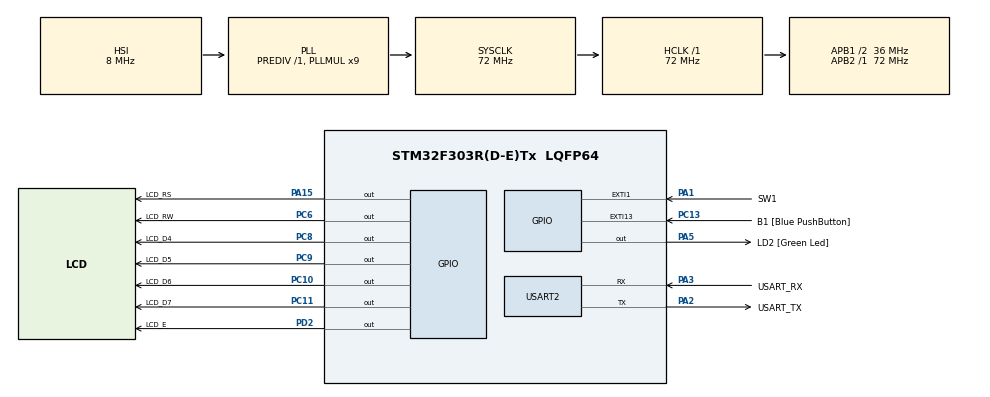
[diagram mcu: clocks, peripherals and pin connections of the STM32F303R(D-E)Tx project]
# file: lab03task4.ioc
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Mcu.Family=STM32F3
Mcu.Name=STM32F303R(D-E)Tx
Mcu.Package=LQFP64
NVIC.EXTI1_IRQn=true\:0\:0\:false\:false\:true\:true\:true\:true
NVIC.PriorityGroup=NVIC_PRIORITYGROUP_0
NVIC.TIM6_DAC_IRQn=true\:0\:0\:false\:false\:true\:true\:true\:true
PA1.GPIO_Label=SW1
PA1.Signal=GPXTI1
PA13.GPIO_Label=TMS
PA13.Mode=Serial_Wire
PA13.Signal=SYS_JTMS-SWDIO
PA14.GPIO_Label=TCK
PA14.Mode=Serial_Wire
PA14.Signal=SYS_JTCK-SWCLK
PA15.GPIO_Label=LCD_RS
PA15.Signal=GPIO_Output
PA2.GPIO_Label=USART_TX
PA2.GPIO_Mode=GPIO_MODE_AF_PP
PA2.GPIO_PuPd=GPIO_NOPULL
PA2.GPIO_Speed=GPIO_SPEED_FREQ_LOW
PA2.Mode=Asynchronous
PA2.Signal=USART2_TX
PA3.GPIO_Label=USART_RX
PA3.GPIO_Mode=GPIO_MODE_AF_PP
PA3.GPIO_PuPd=GPIO_NOPULL
PA3.GPIO_Speed=GPIO_SPEED_FREQ_LOW
PA3.Mode=Asynchronous
PA3.Signal=USART2_RX
PA5.GPIO_Label=LD2 [Green Led]
PA5.GPIO_Mode=GPIO_MODE_OUTPUT_PP
PA5.GPIO_PuPd=GPIO_NOPULL
PA5.GPIO_Speed=GPIO_SPEED_FREQ_LOW
PA5.Signal=GPIO_Output
PB3.GPIO_Label=SWO
PB3.Signal=SYS_JTDO-TRACESWO
PC10.GPIO_Label=LCD_D6
PC10.Signal=GPIO_Output
PC11.GPIO_Label=LCD_D7
PC11.Signal=GPIO_Output
PC13.GPIO_Label=B1 [Blue PushButton]
PC13.GPIO_ModeDefaultEXTI=GPIO_MODE_IT_FALLING
PC13.Signal=GPXTI13
PC14-OSC32_IN.Mode=LSE-External-Oscillator
PC14-OSC32_IN.Signal=RCC_OSC32_IN
PC15-OSC32_OUT.Mode=LSE-External-Oscillator
PC15-OSC32_OUT.Signal=RCC_OSC32_OUT
PC6.GPIO_Label=LCD_RW
PC6.Signal=GPIO_Output
PC8.GPIO_Label=LCD_D4
PC8.Signal=GPIO_Output
PC9.GPIO_Label=LCD_D5
PC9.Signal=GPIO_Output
PD2.GPIO_Label=LCD_E
PD2.Signal=GPIO_Output
PF0-OSC_IN.Mode=HSE-External-Clock-Source
PF0-OSC_IN.Signal=RCC_OSC_IN
PF1-OSC_OUT.Signal=RCC_OSC_OUT
ProjectManager.HeapSize=0x200
ProjectManager.StackSize=0x400
ProjectManager.TargetToolchain=STM32CubeIDE
RCC.AHBFreq_Value=72000000
RCC.APB1CLKDivider=RCC_HCLK_DIV2
RCC.APB1Freq_Value=36000000
RCC.APB1TimFreq_Value=72000000
RCC.APB2Freq_Value=72000000
RCC.APB2TimFreq_Value=72000000
RCC.CortexFreq_Value=72000000
RCC.HCLKFreq_Value=72000000
RCC.HSE_VALUE=8000000
RCC.HSI_VALUE=8000000
RCC.PLLM=8
RCC.PLLMUL=RCC_PLL_MUL9
RCC.PLLN=336
RCC.PLLP=RCC_PLLP_DIV4
RCC.PLLQ=7
RCC.RCC_PLLsource_Clock_Source_FROM_HSE=RCC_HSE_PREDIV_DIV2
RCC.SYSCLKFreq_VALUE=72000000
RCC.SYSCLKSourceVirtual=RCC_SYSCLKSOURCE_PLLCLK
RCC.USBFreq_Value=72000000
TIM6.Period=7199
TIM6.Prescaler=9999
USART2.VirtualMode-Asynchronous=VM_ASYNC
VP_TIM6_VS_ClockSourceINT.Mode=Enable_Timer
board=NUCLEO-F303RE

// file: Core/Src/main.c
/* USER CODE BEGIN Header */
/**
  ******************************************************************************
  * @file           : main.c
  * @brief          : Main program body
  ******************************************************************************
  * @attention
  *
  * Copyright (c) 2024 STMicroelectronics.
  * All rights reserved.
  *
  * This software is licensed under terms that can be found in the LICENSE file
  * in the root directory of this software component.
  * If no LICENSE file comes with this software, it is provided AS-IS.
  *
  ******************************************************************************
  */
/* USER CODE END Header */
#include "main.h"

/* USER CODE BEGIN Includes */
#include <string.h>
#include <stdio.h>
/* USER CODE END Includes */

TIM_HandleTypeDef htim6;

UART_HandleTypeDef huart2;

/* USER CODE BEGIN PV */
//volatile uint32_t startTime = 0;
//volatile uint32_t endTime = 0;
//volatile uint32_t duration = 0;

volatile uint32_t counter = 0;
/* USER CODE END PV */

void SystemClock_Config(void);
static void MX_GPIO_Init(void);
static void MX_USART2_UART_Init(void);
static void MX_TIM6_Init(void);
/* USER CODE BEGIN PFP */
void LCD_putNibble(uint8_t data);
void LCD_enable();
void LCD_command(uint8_t command);
void LCD_data(uint8_t data);
void LCD_display(const char *str);
/* USER CODE END PFP */

int main(void)
{

  /* MCU Configuration--------------------------------------------------------*/

  /* Reset of all peripherals, Initializes the Flash interface and the Systick. */
  HAL_Init();

  /* Configure the system clock */
  SystemClock_Config();

  /* Initialize all configured peripherals */
  MX_GPIO_Init();
  MX_USART2_UART_Init();
  MX_TIM6_Init();
  /* USER CODE BEGIN 2 */
  HAL_Delay(50);
  LCD_putNibble(0b0011);
  LCD_enable();
  LCD_putNibble(0b0011);
  LCD_enable();
  LCD_putNibble(0b0011);
  LCD_enable();
  LCD_putNibble(0b0010);
  LCD_enable();
  LCD_command(0b00101100);
  LCD_command(0b00001000);
  LCD_command(0b00000001);
  LCD_command(0b00000110);
  LCD_command(0b00001111);

  LCD_display("Press SW1/2/3 to Start");
  /* USER CODE END 2 */

  /* Infinite loop */
  while (1)
  {

  }
}

void SystemClock_Config(void)
{
  RCC_OscInitTypeDef RCC_OscInitStruct = {0};
  RCC_ClkInitTypeDef RCC_ClkInitStruct = {0};
  RCC_PeriphCLKInitTypeDef PeriphClkInit = {0};

  /** Initializes the RCC Oscillators according to the specified parameters
  * in the RCC_OscInitTypeDef structure.
  */
  RCC_OscInitStruct.OscillatorType = RCC_OSCILLATORTYPE_HSI;
  RCC_OscInitStruct.HSIState = RCC_HSI_ON;
  RCC_OscInitStruct.HSICalibrationValue = RCC_HSICALIBRATION_DEFAULT;
  RCC_OscInitStruct.PLL.PLLState = RCC_PLL_ON;
  RCC_OscInitStruct.PLL.PLLSource = RCC_PLLSOURCE_HSI;
  RCC_OscInitStruct.PLL.PLLMUL = RCC_PLL_MUL9;
  RCC_OscInitStruct.PLL.PREDIV = RCC_PREDIV_DIV1;
  if (HAL_RCC_OscConfig(&RCC_OscInitStruct) != HAL_OK)
  {
    Error_Handler();
  }

  /** Initializes the CPU, AHB and APB buses clocks
  */
  RCC_ClkInitStruct.ClockType = RCC_CLOCKTYPE_HCLK|RCC_CLOCKTYPE_SYSCLK
                              |RCC_CLOCKTYPE_PCLK1|RCC_CLOCKTYPE_PCLK2;
  RCC_ClkInitStruct.SYSCLKSource = RCC_SYSCLKSOURCE_PLLCLK;
  RCC_ClkInitStruct.AHBCLKDivider = RCC_SYSCLK_DIV1;
  RCC_ClkInitStruct.APB1CLKDivider = RCC_HCLK_DIV2;
  RCC_ClkInitStruct.APB2CLKDivider = RCC_HCLK_DIV1;

  if (HAL_RCC_ClockConfig(&RCC_ClkInitStruct, FLASH_LATENCY_2) != HAL_OK)
  {
    Error_Handler();
  }
  PeriphClkInit.PeriphClockSelection = RCC_PERIPHCLK_USART2;
  PeriphClkInit.Usart2ClockSelection = RCC_USART2CLKSOURCE_PCLK1;
  if (HAL_RCCEx_PeriphCLKConfig(&PeriphClkInit) != HAL_OK)
  {
    Error_Handler();
  }
}

static void MX_TIM6_Init(void)
{

  TIM_MasterConfigTypeDef sMasterConfig = {0};

  htim6.Instance = TIM6;
  htim6.Init.Prescaler = 99;
  htim6.Init.CounterMode = TIM_COUNTERMODE_UP;
  htim6.Init.Period = 719;
  htim6.Init.AutoReloadPreload = TIM_AUTORELOAD_PRELOAD_DISABLE;
  if (HAL_TIM_Base_Init(&htim6) != HAL_OK)
  {
    Error_Handler();
  }
  sMasterConfig.MasterOutputTrigger = TIM_TRGO_RESET;
  sMasterConfig.MasterSlaveMode = TIM_MASTERSLAVEMODE_DISABLE;
  if (HAL_TIMEx_MasterConfigSynchronization(&htim6, &sMasterConfig) != HAL_OK)
  {
    Error_Handler();
  }

}

static void MX_USART2_UART_Init(void)
{

  huart2.Instance = USART2;
  huart2.Init.BaudRate = 38400;
  huart2.Init.WordLength = UART_WORDLENGTH_8B;
  huart2.Init.StopBits = UART_STOPBITS_1;
  huart2.Init.Parity = UART_PARITY_NONE;
  huart2.Init.Mode = UART_MODE_TX_RX;
  huart2.Init.HwFlowCtl = UART_HWCONTROL_NONE;
  huart2.Init.OverSampling = UART_OVERSAMPLING_16;
  huart2.Init.OneBitSampling = UART_ONE_BIT_SAMPLE_DISABLE;
  huart2.AdvancedInit.AdvFeatureInit = UART_ADVFEATURE_NO_INIT;
  if (HAL_UART_Init(&huart2) != HAL_OK)
  {
    Error_Handler();
  }

}

static void MX_GPIO_Init(void)
{
  GPIO_InitTypeDef GPIO_InitStruct = {0};

  /* GPIO Ports Clock Enable */
  __HAL_RCC_GPIOC_CLK_ENABLE();
  __HAL_RCC_GPIOF_CLK_ENABLE();
  __HAL_RCC_GPIOA_CLK_ENABLE();
  __HAL_RCC_GPIOD_CLK_ENABLE();
  __HAL_RCC_GPIOB_CLK_ENABLE();

  /*Configure GPIO pin Output Level */
  HAL_GPIO_WritePin(GPIOA, LD2_Pin|LCD_RS_Pin, GPIO_PIN_RESET);

  /*Configure GPIO pin Output Level */
  HAL_GPIO_WritePin(GPIOC, LCD_RW_Pin|LCD_D4_Pin|LCD_D5_Pin|LCD_D6_Pin
                          |LCD_D7_Pin, GPIO_PIN_RESET);

  /*Configure GPIO pin Output Level */
  HAL_GPIO_WritePin(LCD_E_GPIO_Port, LCD_E_Pin, GPIO_PIN_RESET);

  /*Configure GPIO pin : B1_Pin */
  GPIO_InitStruct.Pin = B1_Pin;
  GPIO_InitStruct.Mode = GPIO_MODE_IT_FALLING;
  GPIO_InitStruct.Pull = GPIO_NOPULL;
  HAL_GPIO_Init(B1_GPIO_Port, &GPIO_InitStruct);

  /*Configure GPIO pin : SW1_Pin */
  GPIO_InitStruct.Pin = SW1_Pin;
  GPIO_InitStruct.Mode = GPIO_MODE_IT_RISING_FALLING;
  GPIO_InitStruct.Pull = GPIO_NOPULL;
  HAL_GPIO_Init(SW1_GPIO_Port, &GPIO_InitStruct);

  /*Configure GPIO pin : SW2_Pin */
  GPIO_InitStruct.Pin = SW2_Pin;
  GPIO_InitStruct.Mode = GPIO_MODE_IT_RISING_FALLING;
  GPIO_InitStruct.Pull = GPIO_NOPULL;
  HAL_GPIO_Init(SW2_GPIO_Port, &GPIO_InitStruct);

  /*Configure GPIO pin : SW3_Pin */
  GPIO_InitStruct.Pin = SW3_Pin;
  GPIO_InitStruct.Mode = GPIO_MODE_IT_RISING_FALLING;
  GPIO_InitStruct.Pull = GPIO_NOPULL;
  HAL_GPIO_Init(SW3_GPIO_Port, &GPIO_InitStruct);

  /*Configure GPIO pins : LD2_Pin LCD_RS_Pin */
  GPIO_InitStruct.Pin = LD2_Pin|LCD_RS_Pin;
  GPIO_InitStruct.Mode = GPIO_MODE_OUTPUT_PP;
  GPIO_InitStruct.Pull = GPIO_NOPULL;
  GPIO_InitStruct.Speed = GPIO_SPEED_FREQ_LOW;
  HAL_GPIO_Init(GPIOA, &GPIO_InitStruct);

  /*Configure GPIO pins : LCD_RW_Pin LCD_D4_Pin LCD_D5_Pin LCD_D6_Pin
                           LCD_D7_Pin */
  GPIO_InitStruct.Pin = LCD_RW_Pin|LCD_D4_Pin|LCD_D5_Pin|LCD_D6_Pin
                          |LCD_D7_Pin;
  GPIO_InitStruct.Mode = GPIO_MODE_OUTPUT_PP;
  GPIO_InitStruct.Pull = GPIO_NOPULL;
  GPIO_InitStruct.Speed = GPIO_SPEED_FREQ_LOW;
  HAL_GPIO_Init(GPIOC, &GPIO_InitStruct);

  /*Configure GPIO pin : LCD_E_Pin */
  GPIO_InitStruct.Pin = LCD_E_Pin;
  GPIO_InitStruct.Mode = GPIO_MODE_OUTPUT_PP;
  GPIO_InitStruct.Pull = GPIO_NOPULL;
  GPIO_InitStruct.Speed = GPIO_SPEED_FREQ_LOW;
  HAL_GPIO_Init(LCD_E_GPIO_Port, &GPIO_InitStruct);

  /* EXTI interrupt init*/
  HAL_NVIC_SetPriority(EXTI1_IRQn, 0, 0);
  HAL_NVIC_EnableIRQ(EXTI1_IRQn);

  /* EXTI interrupt init*/
  HAL_NVIC_SetPriority(EXTI4_IRQn, 0, 0);
  HAL_NVIC_EnableIRQ(EXTI4_IRQn);

  /* EXTI interrupt init*/
  HAL_NVIC_SetPriority(EXTI0_IRQn, 0, 0);
  HAL_NVIC_EnableIRQ(EXTI0_IRQn);

}

/* USER CODE BEGIN 4 */
void HAL_GPIO_EXTI_Callback(uint16_t GPIO_Pin) {
	if (GPIO_Pin == SW1_Pin) {
		if (HAL_GPIO_ReadPin(SW1_GPIO_Port, SW1_Pin) == GPIO_PIN_SET) {
			HAL_TIM_Base_Start_IT(&htim6);
			char temp[20];
			sprintf(temp, "Time: %lu ms", counter);
			LCD_command(0b00000001);	// clear display;
			LCD_display(temp);
		} else {
			counter = 0;
		}
	}
	if (GPIO_Pin == SW2_Pin) {
		if (HAL_GPIO_ReadPin(SW1_GPIO_Port, SW2_Pin) == GPIO_PIN_SET) {
			HAL_TIM_Base_Start_IT(&htim6);
			char temp[20];
			sprintf(temp, "Time: %lu ms", counter);
			LCD_command(0b00000001);	// clear display;
			LCD_display(temp);
		} else {
			counter = 0;
		}
	}
	if (GPIO_Pin == SW3_Pin) {
			if (HAL_GPIO_ReadPin(SW1_GPIO_Port, SW3_Pin) == GPIO_PIN_SET) {
				HAL_TIM_Base_Start_IT(&htim6);
				char temp[20];
				sprintf(temp, "Time: %lu ms", counter);
				LCD_command(0b00000001);	// clear display;
				LCD_display(temp);
			} else {
				counter = 0;
			}
		}
}

void HAL_TIM_PeriodElapsedCallback(TIM_HandleTypeDef *htim) {
    counter++;
}

void LCD_putNibble(uint8_t data) {
	HAL_GPIO_WritePin(LCD_D4_GPIO_Port, LCD_D4_Pin, data & 1);
	HAL_GPIO_WritePin(LCD_D5_GPIO_Port, LCD_D5_Pin, (data >> 1) & 1);
	HAL_GPIO_WritePin(LCD_D6_GPIO_Port, LCD_D6_Pin, (data >> 2) & 1);
	HAL_GPIO_WritePin(LCD_D7_GPIO_Port, LCD_D7_Pin, (data >> 3) & 1);
}

void LCD_enable() {
	HAL_GPIO_WritePin(LCD_E_GPIO_Port, LCD_E_Pin, 1);
	int delayCounter = 10000;
	while(delayCounter--);
	HAL_GPIO_WritePin(LCD_E_GPIO_Port, LCD_E_Pin, 0);
	delayCounter = 10000;
	while(delayCounter--);
}

void LCD_command(uint8_t command) {
	HAL_GPIO_WritePin(LCD_RS_GPIO_Port, LCD_RS_Pin, 0);
	LCD_putNibble(command >> 4);
	LCD_enable();
	LCD_putNibble(command & 0x0f);
	LCD_enable();
}

void LCD_data(uint8_t data) {
	HAL_GPIO_WritePin(LCD_RS_GPIO_Port, LCD_RS_Pin, 1);
	int delayCounter = 10000;
	while(delayCounter--);
	LCD_putNibble(data >> 4);
	LCD_enable();
	LCD_putNibble(data & 0x0f);
	LCD_enable();
	HAL_GPIO_WritePin(LCD_RS_GPIO_Port, LCD_RS_Pin, 0);
}

void LCD_display(const char *str) {

	int c = 0;
	while(*str) {
		if (c == 16) {
			LCD_command(0b11000000);
		}
		LCD_data(*str++);
		c++;
	}

}
/* USER CODE END 4 */

void Error_Handler(void)
{
  __disable_irq();
  while (1)
  {
  }
}
